VERSION 5.8 ;
BUSBITCHARS "[]" ;
DIVIDERCHAR "/" ;

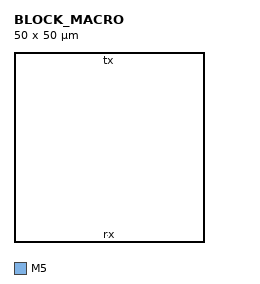
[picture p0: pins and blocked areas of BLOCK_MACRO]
MACRO BLOCK_MACRO
  CLASS BLOCK ;
  SIZE 50 BY 50 ;
  PIN tx
    DIRECTION OUTPUT ;
    PORT
      LAYER M5 ;
      RECT 24.5 47.5 25.5 48.5 ;
    END
  END tx
  PIN rx
    DIRECTION INPUT ;
    PORT
      LAYER M5 ;
      RECT 24.5 1.5 25.5 2.5 ;
    END
  END rx
END BLOCK_MACRO

END LIBRARY
